VERSION 5.8 ;
BUSBITCHARS "[]" ;
DIVIDERCHAR "/" ;
UNITS
    DATABASE MICRONS 1000 ;
END UNITS

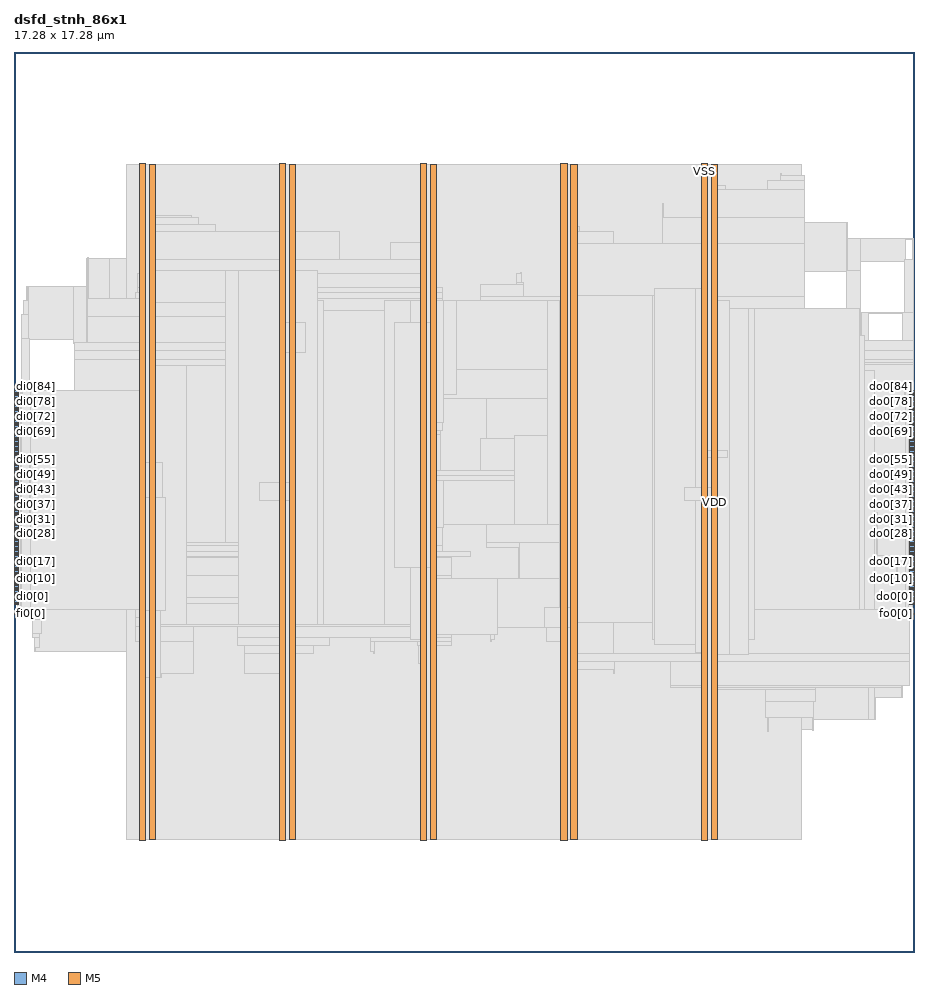
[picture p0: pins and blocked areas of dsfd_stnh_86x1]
MACRO dsfd_stnh_86x1
  FOREIGN dsfd_stnh_86x1 0 0 ;
  CLASS BLOCK ;
  SIZE 17.28 BY 17.28 ;
  PIN di0[0]
    DIRECTION INPUT ;
    USE SIGNAL ;
    PORT
      LAYER M4 ;
        RECT  0 6.672 0.084 6.696 ;
    END
  END di0[0]
  PIN di0[10]
    DIRECTION INPUT ;
    USE SIGNAL ;
    PORT
      LAYER M4 ;
        RECT  0 7.152 0.084 7.176 ;
    END
  END di0[10]
  PIN di0[11]
    DIRECTION INPUT ;
    USE SIGNAL ;
    PORT
      LAYER M4 ;
        RECT  0 7.2 0.084 7.224 ;
    END
  END di0[11]
  PIN di0[12]
    DIRECTION INPUT ;
    USE SIGNAL ;
    PORT
      LAYER M4 ;
        RECT  0 7.248 0.084 7.272 ;
    END
  END di0[12]
  PIN di0[13]
    DIRECTION INPUT ;
    USE SIGNAL ;
    PORT
      LAYER M4 ;
        RECT  0 7.296 0.084 7.32 ;
    END
  END di0[13]
  PIN di0[14]
    DIRECTION INPUT ;
    USE SIGNAL ;
    PORT
      LAYER M4 ;
        RECT  0 7.344 0.084 7.368 ;
    END
  END di0[14]
  PIN di0[15]
    DIRECTION INPUT ;
    USE SIGNAL ;
    PORT
      LAYER M4 ;
        RECT  0 7.392 0.084 7.416 ;
    END
  END di0[15]
  PIN di0[16]
    DIRECTION INPUT ;
    USE SIGNAL ;
    PORT
      LAYER M4 ;
        RECT  0 7.44 0.084 7.464 ;
    END
  END di0[16]
  PIN di0[17]
    DIRECTION INPUT ;
    USE SIGNAL ;
    PORT
      LAYER M4 ;
        RECT  0 7.488 0.084 7.512 ;
    END
  END di0[17]
  PIN di0[18]
    DIRECTION INPUT ;
    USE SIGNAL ;
    PORT
      LAYER M4 ;
        RECT  0 7.536 0.084 7.56 ;
    END
  END di0[18]
  PIN di0[19]
    DIRECTION INPUT ;
    USE SIGNAL ;
    PORT
      LAYER M4 ;
        RECT  0 7.584 0.084 7.608 ;
    END
  END di0[19]
  PIN di0[1]
    DIRECTION INPUT ;
    USE SIGNAL ;
    PORT
      LAYER M4 ;
        RECT  0 6.72 0.084 6.744 ;
    END
  END di0[1]
  PIN di0[20]
    DIRECTION INPUT ;
    USE SIGNAL ;
    PORT
      LAYER M4 ;
        RECT  0 7.632 0.084 7.656 ;
    END
  END di0[20]
  PIN di0[21]
    DIRECTION INPUT ;
    USE SIGNAL ;
    PORT
      LAYER M4 ;
        RECT  0 7.68 0.084 7.704 ;
    END
  END di0[21]
  PIN di0[22]
    DIRECTION INPUT ;
    USE SIGNAL ;
    PORT
      LAYER M4 ;
        RECT  0 7.728 0.084 7.752 ;
    END
  END di0[22]
  PIN di0[23]
    DIRECTION INPUT ;
    USE SIGNAL ;
    PORT
      LAYER M4 ;
        RECT  0 7.776 0.084 7.8 ;
    END
  END di0[23]
  PIN di0[24]
    DIRECTION INPUT ;
    USE SIGNAL ;
    PORT
      LAYER M4 ;
        RECT  0 7.824 0.084 7.848 ;
    END
  END di0[24]
  PIN di0[25]
    DIRECTION INPUT ;
    USE SIGNAL ;
    PORT
      LAYER M4 ;
        RECT  0 7.872 0.084 7.896 ;
    END
  END di0[25]
  PIN di0[26]
    DIRECTION INPUT ;
    USE SIGNAL ;
    PORT
      LAYER M4 ;
        RECT  0 7.92 0.084 7.944 ;
    END
  END di0[26]
  PIN di0[27]
    DIRECTION INPUT ;
    USE SIGNAL ;
    PORT
      LAYER M4 ;
        RECT  0 7.968 0.084 7.992 ;
    END
  END di0[27]
  PIN di0[28]
    DIRECTION INPUT ;
    USE SIGNAL ;
    PORT
      LAYER M4 ;
        RECT  0 8.016 0.084 8.04 ;
    END
  END di0[28]
  PIN di0[29]
    DIRECTION INPUT ;
    USE SIGNAL ;
    PORT
      LAYER M4 ;
        RECT  0 8.064 0.084 8.088 ;
    END
  END di0[29]
  PIN di0[2]
    DIRECTION INPUT ;
    USE SIGNAL ;
    PORT
      LAYER M4 ;
        RECT  0 6.768 0.084 6.792 ;
    END
  END di0[2]
  PIN di0[30]
    DIRECTION INPUT ;
    USE SIGNAL ;
    PORT
      LAYER M4 ;
        RECT  0 8.112 0.084 8.136 ;
    END
  END di0[30]
  PIN di0[31]
    DIRECTION INPUT ;
    USE SIGNAL ;
    PORT
      LAYER M4 ;
        RECT  0 8.16 0.084 8.184 ;
    END
  END di0[31]
  PIN di0[32]
    DIRECTION INPUT ;
    USE SIGNAL ;
    PORT
      LAYER M4 ;
        RECT  0 8.208 0.084 8.232 ;
    END
  END di0[32]
  PIN di0[33]
    DIRECTION INPUT ;
    USE SIGNAL ;
    PORT
      LAYER M4 ;
        RECT  0 8.256 0.084 8.28 ;
    END
  END di0[33]
  PIN di0[34]
    DIRECTION INPUT ;
    USE SIGNAL ;
    PORT
      LAYER M4 ;
        RECT  0 8.304 0.084 8.328 ;
    END
  END di0[34]
  PIN di0[35]
    DIRECTION INPUT ;
    USE SIGNAL ;
    PORT
      LAYER M4 ;
        RECT  0 8.352 0.084 8.376 ;
    END
  END di0[35]
  PIN di0[36]
    DIRECTION INPUT ;
    USE SIGNAL ;
    PORT
      LAYER M4 ;
        RECT  0 8.4 0.084 8.424 ;
    END
  END di0[36]
  PIN di0[37]
    DIRECTION INPUT ;
    USE SIGNAL ;
    PORT
      LAYER M4 ;
        RECT  0 8.448 0.084 8.472 ;
    END
  END di0[37]
  PIN di0[38]
    DIRECTION INPUT ;
    USE SIGNAL ;
    PORT
      LAYER M4 ;
        RECT  0 8.496 0.084 8.52 ;
    END
  END di0[38]
  PIN di0[39]
    DIRECTION INPUT ;
    USE SIGNAL ;
    PORT
      LAYER M4 ;
        RECT  0 8.544 0.084 8.568 ;
    END
  END di0[39]
  PIN di0[3]
    DIRECTION INPUT ;
    USE SIGNAL ;
    PORT
      LAYER M4 ;
        RECT  0 6.816 0.084 6.84 ;
    END
  END di0[3]
  PIN di0[40]
    DIRECTION INPUT ;
    USE SIGNAL ;
    PORT
      LAYER M4 ;
        RECT  0 8.592 0.084 8.616 ;
    END
  END di0[40]
  PIN di0[41]
    DIRECTION INPUT ;
    USE SIGNAL ;
    PORT
      LAYER M4 ;
        RECT  0 8.64 0.084 8.664 ;
    END
  END di0[41]
  PIN di0[42]
    DIRECTION INPUT ;
    USE SIGNAL ;
    PORT
      LAYER M4 ;
        RECT  0 8.688 0.084 8.712 ;
    END
  END di0[42]
  PIN di0[43]
    DIRECTION INPUT ;
    USE SIGNAL ;
    PORT
      LAYER M4 ;
        RECT  0 8.736 0.084 8.76 ;
    END
  END di0[43]
  PIN di0[44]
    DIRECTION INPUT ;
    USE SIGNAL ;
    PORT
      LAYER M4 ;
        RECT  0 8.784 0.084 8.808 ;
    END
  END di0[44]
  PIN di0[45]
    DIRECTION INPUT ;
    USE SIGNAL ;
    PORT
      LAYER M4 ;
        RECT  0 8.832 0.084 8.856 ;
    END
  END di0[45]
  PIN di0[46]
    DIRECTION INPUT ;
    USE SIGNAL ;
    PORT
      LAYER M4 ;
        RECT  0 8.88 0.084 8.904 ;
    END
  END di0[46]
  PIN di0[47]
    DIRECTION INPUT ;
    USE SIGNAL ;
    PORT
      LAYER M4 ;
        RECT  0 8.928 0.084 8.952 ;
    END
  END di0[47]
  PIN di0[48]
    DIRECTION INPUT ;
    USE SIGNAL ;
    PORT
      LAYER M4 ;
        RECT  0 8.976 0.084 9 ;
    END
  END di0[48]
  PIN di0[49]
    DIRECTION INPUT ;
    USE SIGNAL ;
    PORT
      LAYER M4 ;
        RECT  0 9.024 0.084 9.048 ;
    END
  END di0[49]
  PIN di0[4]
    DIRECTION INPUT ;
    USE SIGNAL ;
    PORT
      LAYER M4 ;
        RECT  0 6.864 0.084 6.888 ;
    END
  END di0[4]
  PIN di0[50]
    DIRECTION INPUT ;
    USE SIGNAL ;
    PORT
      LAYER M4 ;
        RECT  0 9.072 0.084 9.096 ;
    END
  END di0[50]
  PIN di0[51]
    DIRECTION INPUT ;
    USE SIGNAL ;
    PORT
      LAYER M4 ;
        RECT  0 9.12 0.084 9.144 ;
    END
  END di0[51]
  PIN di0[52]
    DIRECTION INPUT ;
    USE SIGNAL ;
    PORT
      LAYER M4 ;
        RECT  0 9.168 0.084 9.192 ;
    END
  END di0[52]
  PIN di0[53]
    DIRECTION INPUT ;
    USE SIGNAL ;
    PORT
      LAYER M4 ;
        RECT  0 9.216 0.084 9.24 ;
    END
  END di0[53]
  PIN di0[54]
    DIRECTION INPUT ;
    USE SIGNAL ;
    PORT
      LAYER M4 ;
        RECT  0 9.264 0.084 9.288 ;
    END
  END di0[54]
  PIN di0[55]
    DIRECTION INPUT ;
    USE SIGNAL ;
    PORT
      LAYER M4 ;
        RECT  0 9.312 0.084 9.336 ;
    END
  END di0[55]
  PIN di0[56]
    DIRECTION INPUT ;
    USE SIGNAL ;
    PORT
      LAYER M4 ;
        RECT  0 9.36 0.084 9.384 ;
    END
  END di0[56]
  PIN di0[57]
    DIRECTION INPUT ;
    USE SIGNAL ;
    PORT
      LAYER M4 ;
        RECT  0 9.408 0.084 9.432 ;
    END
  END di0[57]
  PIN di0[58]
    DIRECTION INPUT ;
    USE SIGNAL ;
    PORT
      LAYER M4 ;
        RECT  0 9.456 0.084 9.48 ;
    END
  END di0[58]
  PIN di0[59]
    DIRECTION INPUT ;
    USE SIGNAL ;
    PORT
      LAYER M4 ;
        RECT  0 9.504 0.084 9.528 ;
    END
  END di0[59]
  PIN di0[5]
    DIRECTION INPUT ;
    USE SIGNAL ;
    PORT
      LAYER M4 ;
        RECT  0 6.912 0.084 6.936 ;
    END
  END di0[5]
  PIN di0[60]
    DIRECTION INPUT ;
    USE SIGNAL ;
    PORT
      LAYER M4 ;
        RECT  0 9.552 0.084 9.576 ;
    END
  END di0[60]
  PIN di0[61]
    DIRECTION INPUT ;
    USE SIGNAL ;
    PORT
      LAYER M4 ;
        RECT  0 9.6 0.084 9.624 ;
    END
  END di0[61]
  PIN di0[62]
    DIRECTION INPUT ;
    USE SIGNAL ;
    PORT
      LAYER M4 ;
        RECT  0 9.648 0.084 9.672 ;
    END
  END di0[62]
  PIN di0[63]
    DIRECTION INPUT ;
    USE SIGNAL ;
    PORT
      LAYER M4 ;
        RECT  0 9.696 0.084 9.72 ;
    END
  END di0[63]
  PIN di0[64]
    DIRECTION INPUT ;
    USE SIGNAL ;
    PORT
      LAYER M4 ;
        RECT  0 9.744 0.084 9.768 ;
    END
  END di0[64]
  PIN di0[65]
    DIRECTION INPUT ;
    USE SIGNAL ;
    PORT
      LAYER M4 ;
        RECT  0 9.792 0.084 9.816 ;
    END
  END di0[65]
  PIN di0[66]
    DIRECTION INPUT ;
    USE SIGNAL ;
    PORT
      LAYER M4 ;
        RECT  0 9.84 0.084 9.864 ;
    END
  END di0[66]
  PIN di0[67]
    DIRECTION INPUT ;
    USE SIGNAL ;
    PORT
      LAYER M4 ;
        RECT  0 9.888 0.084 9.912 ;
    END
  END di0[67]
  PIN di0[68]
    DIRECTION INPUT ;
    USE SIGNAL ;
    PORT
      LAYER M4 ;
        RECT  0 9.936 0.084 9.96 ;
    END
  END di0[68]
  PIN di0[69]
    DIRECTION INPUT ;
    USE SIGNAL ;
    PORT
      LAYER M4 ;
        RECT  0 9.984 0.084 10.008 ;
    END
  END di0[69]
  PIN di0[6]
    DIRECTION INPUT ;
    USE SIGNAL ;
    PORT
      LAYER M4 ;
        RECT  0 6.96 0.084 6.984 ;
    END
  END di0[6]
  PIN di0[70]
    DIRECTION INPUT ;
    USE SIGNAL ;
    PORT
      LAYER M4 ;
        RECT  0 10.032 0.084 10.056 ;
    END
  END di0[70]
  PIN di0[71]
    DIRECTION INPUT ;
    USE SIGNAL ;
    PORT
      LAYER M4 ;
        RECT  0 10.08 0.084 10.104 ;
    END
  END di0[71]
  PIN di0[72]
    DIRECTION INPUT ;
    USE SIGNAL ;
    PORT
      LAYER M4 ;
        RECT  0 10.128 0.084 10.152 ;
    END
  END di0[72]
  PIN di0[73]
    DIRECTION INPUT ;
    USE SIGNAL ;
    PORT
      LAYER M4 ;
        RECT  0 10.176 0.084 10.2 ;
    END
  END di0[73]
  PIN di0[74]
    DIRECTION INPUT ;
    USE SIGNAL ;
    PORT
      LAYER M4 ;
        RECT  0 10.224 0.084 10.248 ;
    END
  END di0[74]
  PIN di0[75]
    DIRECTION INPUT ;
    USE SIGNAL ;
    PORT
      LAYER M4 ;
        RECT  0 10.272 0.084 10.296 ;
    END
  END di0[75]
  PIN di0[76]
    DIRECTION INPUT ;
    USE SIGNAL ;
    PORT
      LAYER M4 ;
        RECT  0 10.32 0.084 10.344 ;
    END
  END di0[76]
  PIN di0[77]
    DIRECTION INPUT ;
    USE SIGNAL ;
    PORT
      LAYER M4 ;
        RECT  0 10.368 0.084 10.392 ;
    END
  END di0[77]
  PIN di0[78]
    DIRECTION INPUT ;
    USE SIGNAL ;
    PORT
      LAYER M4 ;
        RECT  0 10.416 0.084 10.44 ;
    END
  END di0[78]
  PIN di0[79]
    DIRECTION INPUT ;
    USE SIGNAL ;
    PORT
      LAYER M4 ;
        RECT  0 10.464 0.084 10.488 ;
    END
  END di0[79]
  PIN di0[7]
    DIRECTION INPUT ;
    USE SIGNAL ;
    PORT
      LAYER M4 ;
        RECT  0 7.008 0.084 7.032 ;
    END
  END di0[7]
  PIN di0[80]
    DIRECTION INPUT ;
    USE SIGNAL ;
    PORT
      LAYER M4 ;
        RECT  0 10.512 0.084 10.536 ;
    END
  END di0[80]
  PIN di0[81]
    DIRECTION INPUT ;
    USE SIGNAL ;
    PORT
      LAYER M4 ;
        RECT  0 10.56 0.084 10.584 ;
    END
  END di0[81]
  PIN di0[82]
    DIRECTION INPUT ;
    USE SIGNAL ;
    PORT
      LAYER M4 ;
        RECT  0 10.608 0.084 10.632 ;
    END
  END di0[82]
  PIN di0[83]
    DIRECTION INPUT ;
    USE SIGNAL ;
    PORT
      LAYER M4 ;
        RECT  0 10.656 0.084 10.68 ;
    END
  END di0[83]
  PIN di0[84]
    DIRECTION INPUT ;
    USE SIGNAL ;
    PORT
      LAYER M4 ;
        RECT  0 10.704 0.084 10.728 ;
    END
  END di0[84]
  PIN di0[85]
    DIRECTION INPUT ;
    USE SIGNAL ;
    PORT
      LAYER M4 ;
        RECT  0 10.752 0.084 10.776 ;
    END
  END di0[85]
  PIN di0[8]
    DIRECTION INPUT ;
    USE SIGNAL ;
    PORT
      LAYER M4 ;
        RECT  0 7.056 0.084 7.08 ;
    END
  END di0[8]
  PIN di0[9]
    DIRECTION INPUT ;
    USE SIGNAL ;
    PORT
      LAYER M4 ;
        RECT  0 7.104 0.084 7.128 ;
    END
  END di0[9]
  PIN do0[0]
    DIRECTION OUTPUT ;
    USE SIGNAL ;
    PORT
      LAYER M4 ;
        RECT  17.196 6.672 17.28 6.696 ;
    END
  END do0[0]
  PIN do0[10]
    DIRECTION OUTPUT ;
    USE SIGNAL ;
    PORT
      LAYER M4 ;
        RECT  17.196 7.152 17.28 7.176 ;
    END
  END do0[10]
  PIN do0[11]
    DIRECTION OUTPUT ;
    USE SIGNAL ;
    PORT
      LAYER M4 ;
        RECT  17.196 7.2 17.28 7.224 ;
    END
  END do0[11]
  PIN do0[12]
    DIRECTION OUTPUT ;
    USE SIGNAL ;
    PORT
      LAYER M4 ;
        RECT  17.196 7.248 17.28 7.272 ;
    END
  END do0[12]
  PIN do0[13]
    DIRECTION OUTPUT ;
    USE SIGNAL ;
    PORT
      LAYER M4 ;
        RECT  17.196 7.296 17.28 7.32 ;
    END
  END do0[13]
  PIN do0[14]
    DIRECTION OUTPUT ;
    USE SIGNAL ;
    PORT
      LAYER M4 ;
        RECT  17.196 7.344 17.28 7.368 ;
    END
  END do0[14]
  PIN do0[15]
    DIRECTION OUTPUT ;
    USE SIGNAL ;
    PORT
      LAYER M4 ;
        RECT  17.196 7.392 17.28 7.416 ;
    END
  END do0[15]
  PIN do0[16]
    DIRECTION OUTPUT ;
    USE SIGNAL ;
    PORT
      LAYER M4 ;
        RECT  17.196 7.44 17.28 7.464 ;
    END
  END do0[16]
  PIN do0[17]
    DIRECTION OUTPUT ;
    USE SIGNAL ;
    PORT
      LAYER M4 ;
        RECT  17.196 7.488 17.28 7.512 ;
    END
  END do0[17]
  PIN do0[18]
    DIRECTION OUTPUT ;
    USE SIGNAL ;
    PORT
      LAYER M4 ;
        RECT  17.196 7.536 17.28 7.56 ;
    END
  END do0[18]
  PIN do0[19]
    DIRECTION OUTPUT ;
    USE SIGNAL ;
    PORT
      LAYER M4 ;
        RECT  17.196 7.584 17.28 7.608 ;
    END
  END do0[19]
  PIN do0[1]
    DIRECTION OUTPUT ;
    USE SIGNAL ;
    PORT
      LAYER M4 ;
        RECT  17.196 6.72 17.28 6.744 ;
    END
  END do0[1]
  PIN do0[20]
    DIRECTION OUTPUT ;
    USE SIGNAL ;
    PORT
      LAYER M4 ;
        RECT  17.196 7.632 17.28 7.656 ;
    END
  END do0[20]
  PIN do0[21]
    DIRECTION OUTPUT ;
    USE SIGNAL ;
    PORT
      LAYER M4 ;
        RECT  17.196 7.68 17.28 7.704 ;
    END
  END do0[21]
  PIN do0[22]
    DIRECTION OUTPUT ;
    USE SIGNAL ;
    PORT
      LAYER M4 ;
        RECT  17.196 7.728 17.28 7.752 ;
    END
  END do0[22]
  PIN do0[23]
    DIRECTION OUTPUT ;
    USE SIGNAL ;
    PORT
      LAYER M4 ;
        RECT  17.196 7.776 17.28 7.8 ;
    END
  END do0[23]
  PIN do0[24]
    DIRECTION OUTPUT ;
    USE SIGNAL ;
    PORT
      LAYER M4 ;
        RECT  17.196 7.824 17.28 7.848 ;
    END
  END do0[24]
  PIN do0[25]
    DIRECTION OUTPUT ;
    USE SIGNAL ;
    PORT
      LAYER M4 ;
        RECT  17.196 7.872 17.28 7.896 ;
    END
  END do0[25]
  PIN do0[26]
    DIRECTION OUTPUT ;
    USE SIGNAL ;
    PORT
      LAYER M4 ;
        RECT  17.196 7.92 17.28 7.944 ;
    END
  END do0[26]
  PIN do0[27]
    DIRECTION OUTPUT ;
    USE SIGNAL ;
    PORT
      LAYER M4 ;
        RECT  17.196 7.968 17.28 7.992 ;
    END
  END do0[27]
  PIN do0[28]
    DIRECTION OUTPUT ;
    USE SIGNAL ;
    PORT
      LAYER M4 ;
        RECT  17.196 8.016 17.28 8.04 ;
    END
  END do0[28]
  PIN do0[29]
    DIRECTION OUTPUT ;
    USE SIGNAL ;
    PORT
      LAYER M4 ;
        RECT  17.196 8.064 17.28 8.088 ;
    END
  END do0[29]
  PIN do0[2]
    DIRECTION OUTPUT ;
    USE SIGNAL ;
    PORT
      LAYER M4 ;
        RECT  17.196 6.768 17.28 6.792 ;
    END
  END do0[2]
  PIN do0[30]
    DIRECTION OUTPUT ;
    USE SIGNAL ;
    PORT
      LAYER M4 ;
        RECT  17.196 8.112 17.28 8.136 ;
    END
  END do0[30]
  PIN do0[31]
    DIRECTION OUTPUT ;
    USE SIGNAL ;
    PORT
      LAYER M4 ;
        RECT  17.196 8.16 17.28 8.184 ;
    END
  END do0[31]
  PIN do0[32]
    DIRECTION OUTPUT ;
    USE SIGNAL ;
    PORT
      LAYER M4 ;
        RECT  17.196 8.208 17.28 8.232 ;
    END
  END do0[32]
  PIN do0[33]
    DIRECTION OUTPUT ;
    USE SIGNAL ;
    PORT
      LAYER M4 ;
        RECT  17.196 8.256 17.28 8.28 ;
    END
  END do0[33]
  PIN do0[34]
    DIRECTION OUTPUT ;
    USE SIGNAL ;
    PORT
      LAYER M4 ;
        RECT  17.196 8.304 17.28 8.328 ;
    END
  END do0[34]
  PIN do0[35]
    DIRECTION OUTPUT ;
    USE SIGNAL ;
    PORT
      LAYER M4 ;
        RECT  17.196 8.352 17.28 8.376 ;
    END
  END do0[35]
  PIN do0[36]
    DIRECTION OUTPUT ;
    USE SIGNAL ;
    PORT
      LAYER M4 ;
        RECT  17.196 8.4 17.28 8.424 ;
    END
  END do0[36]
  PIN do0[37]
    DIRECTION OUTPUT ;
    USE SIGNAL ;
    PORT
      LAYER M4 ;
        RECT  17.196 8.448 17.28 8.472 ;
    END
  END do0[37]
  PIN do0[38]
    DIRECTION OUTPUT ;
    USE SIGNAL ;
    PORT
      LAYER M4 ;
        RECT  17.196 8.496 17.28 8.52 ;
    END
  END do0[38]
  PIN do0[39]
    DIRECTION OUTPUT ;
    USE SIGNAL ;
    PORT
      LAYER M4 ;
        RECT  17.196 8.544 17.28 8.568 ;
    END
  END do0[39]
  PIN do0[3]
    DIRECTION OUTPUT ;
    USE SIGNAL ;
    PORT
      LAYER M4 ;
        RECT  17.196 6.816 17.28 6.84 ;
    END
  END do0[3]
  PIN do0[40]
    DIRECTION OUTPUT ;
    USE SIGNAL ;
    PORT
      LAYER M4 ;
        RECT  17.196 8.592 17.28 8.616 ;
    END
  END do0[40]
  PIN do0[41]
    DIRECTION OUTPUT ;
    USE SIGNAL ;
    PORT
      LAYER M4 ;
        RECT  17.196 8.64 17.28 8.664 ;
    END
  END do0[41]
  PIN do0[42]
    DIRECTION OUTPUT ;
    USE SIGNAL ;
    PORT
      LAYER M4 ;
        RECT  17.196 8.688 17.28 8.712 ;
    END
  END do0[42]
  PIN do0[43]
    DIRECTION OUTPUT ;
    USE SIGNAL ;
    PORT
      LAYER M4 ;
        RECT  17.196 8.736 17.28 8.76 ;
    END
  END do0[43]
  PIN do0[44]
    DIRECTION OUTPUT ;
    USE SIGNAL ;
    PORT
      LAYER M4 ;
        RECT  17.196 8.784 17.28 8.808 ;
    END
  END do0[44]
  PIN do0[45]
    DIRECTION OUTPUT ;
    USE SIGNAL ;
    PORT
      LAYER M4 ;
        RECT  17.196 8.832 17.28 8.856 ;
    END
  END do0[45]
  PIN do0[46]
    DIRECTION OUTPUT ;
    USE SIGNAL ;
    PORT
      LAYER M4 ;
        RECT  17.196 8.88 17.28 8.904 ;
    END
  END do0[46]
  PIN do0[47]
    DIRECTION OUTPUT ;
    USE SIGNAL ;
    PORT
      LAYER M4 ;
        RECT  17.196 8.928 17.28 8.952 ;
    END
  END do0[47]
  PIN do0[48]
    DIRECTION OUTPUT ;
    USE SIGNAL ;
    PORT
      LAYER M4 ;
        RECT  17.196 8.976 17.28 9 ;
    END
  END do0[48]
  PIN do0[49]
    DIRECTION OUTPUT ;
    USE SIGNAL ;
    PORT
      LAYER M4 ;
        RECT  17.196 9.024 17.28 9.048 ;
    END
  END do0[49]
  PIN do0[4]
    DIRECTION OUTPUT ;
    USE SIGNAL ;
    PORT
      LAYER M4 ;
        RECT  17.196 6.864 17.28 6.888 ;
    END
  END do0[4]
  PIN do0[50]
    DIRECTION OUTPUT ;
    USE SIGNAL ;
    PORT
      LAYER M4 ;
        RECT  17.196 9.072 17.28 9.096 ;
    END
  END do0[50]
  PIN do0[51]
    DIRECTION OUTPUT ;
    USE SIGNAL ;
    PORT
      LAYER M4 ;
        RECT  17.196 9.12 17.28 9.144 ;
    END
  END do0[51]
  PIN do0[52]
    DIRECTION OUTPUT ;
    USE SIGNAL ;
    PORT
      LAYER M4 ;
        RECT  17.196 9.168 17.28 9.192 ;
    END
  END do0[52]
  PIN do0[53]
    DIRECTION OUTPUT ;
    USE SIGNAL ;
    PORT
      LAYER M4 ;
        RECT  17.196 9.216 17.28 9.24 ;
    END
  END do0[53]
  PIN do0[54]
    DIRECTION OUTPUT ;
    USE SIGNAL ;
    PORT
      LAYER M4 ;
        RECT  17.196 9.264 17.28 9.288 ;
    END
  END do0[54]
  PIN do0[55]
    DIRECTION OUTPUT ;
    USE SIGNAL ;
    PORT
      LAYER M4 ;
        RECT  17.196 9.312 17.28 9.336 ;
    END
  END do0[55]
  PIN do0[56]
    DIRECTION OUTPUT ;
    USE SIGNAL ;
    PORT
      LAYER M4 ;
        RECT  17.196 9.36 17.28 9.384 ;
    END
  END do0[56]
  PIN do0[57]
    DIRECTION OUTPUT ;
    USE SIGNAL ;
    PORT
      LAYER M4 ;
        RECT  17.196 9.408 17.28 9.432 ;
    END
  END do0[57]
  PIN do0[58]
    DIRECTION OUTPUT ;
    USE SIGNAL ;
    PORT
      LAYER M4 ;
        RECT  17.196 9.456 17.28 9.48 ;
    END
  END do0[58]
  PIN do0[59]
    DIRECTION OUTPUT ;
    USE SIGNAL ;
    PORT
      LAYER M4 ;
        RECT  17.196 9.504 17.28 9.528 ;
    END
  END do0[59]
  PIN do0[5]
    DIRECTION OUTPUT ;
    USE SIGNAL ;
    PORT
      LAYER M4 ;
        RECT  17.196 6.912 17.28 6.936 ;
    END
  END do0[5]
  PIN do0[60]
    DIRECTION OUTPUT ;
    USE SIGNAL ;
    PORT
      LAYER M4 ;
        RECT  17.196 9.552 17.28 9.576 ;
    END
  END do0[60]
  PIN do0[61]
    DIRECTION OUTPUT ;
    USE SIGNAL ;
    PORT
      LAYER M4 ;
        RECT  17.196 9.6 17.28 9.624 ;
    END
  END do0[61]
  PIN do0[62]
    DIRECTION OUTPUT ;
    USE SIGNAL ;
    PORT
      LAYER M4 ;
        RECT  17.196 9.648 17.28 9.672 ;
    END
  END do0[62]
  PIN do0[63]
    DIRECTION OUTPUT ;
    USE SIGNAL ;
    PORT
      LAYER M4 ;
        RECT  17.196 9.696 17.28 9.72 ;
    END
  END do0[63]
  PIN do0[64]
    DIRECTION OUTPUT ;
    USE SIGNAL ;
    PORT
      LAYER M4 ;
        RECT  17.196 9.744 17.28 9.768 ;
    END
  END do0[64]
  PIN do0[65]
    DIRECTION OUTPUT ;
    USE SIGNAL ;
    PORT
      LAYER M4 ;
        RECT  17.196 9.792 17.28 9.816 ;
    END
  END do0[65]
  PIN do0[66]
    DIRECTION OUTPUT ;
    USE SIGNAL ;
    PORT
      LAYER M4 ;
        RECT  17.196 9.84 17.28 9.864 ;
    END
  END do0[66]
  PIN do0[67]
    DIRECTION OUTPUT ;
    USE SIGNAL ;
    PORT
      LAYER M4 ;
        RECT  17.196 9.888 17.28 9.912 ;
    END
  END do0[67]
  PIN do0[68]
    DIRECTION OUTPUT ;
    USE SIGNAL ;
    PORT
      LAYER M4 ;
        RECT  17.196 9.936 17.28 9.96 ;
    END
  END do0[68]
  PIN do0[69]
    DIRECTION OUTPUT ;
    USE SIGNAL ;
    PORT
      LAYER M4 ;
        RECT  17.196 9.984 17.28 10.008 ;
    END
  END do0[69]
  PIN do0[6]
    DIRECTION OUTPUT ;
    USE SIGNAL ;
    PORT
      LAYER M4 ;
        RECT  17.196 6.96 17.28 6.984 ;
    END
  END do0[6]
  PIN do0[70]
    DIRECTION OUTPUT ;
    USE SIGNAL ;
    PORT
      LAYER M4 ;
        RECT  17.196 10.032 17.28 10.056 ;
    END
  END do0[70]
  PIN do0[71]
    DIRECTION OUTPUT ;
    USE SIGNAL ;
    PORT
      LAYER M4 ;
        RECT  17.196 10.08 17.28 10.104 ;
    END
  END do0[71]
  PIN do0[72]
    DIRECTION OUTPUT ;
    USE SIGNAL ;
    PORT
      LAYER M4 ;
        RECT  17.196 10.128 17.28 10.152 ;
    END
  END do0[72]
  PIN do0[73]
    DIRECTION OUTPUT ;
    USE SIGNAL ;
    PORT
      LAYER M4 ;
        RECT  17.196 10.176 17.28 10.2 ;
    END
  END do0[73]
  PIN do0[74]
    DIRECTION OUTPUT ;
    USE SIGNAL ;
    PORT
      LAYER M4 ;
        RECT  17.196 10.224 17.28 10.248 ;
    END
  END do0[74]
  PIN do0[75]
    DIRECTION OUTPUT ;
    USE SIGNAL ;
    PORT
      LAYER M4 ;
        RECT  17.196 10.272 17.28 10.296 ;
    END
  END do0[75]
  PIN do0[76]
    DIRECTION OUTPUT ;
    USE SIGNAL ;
    PORT
      LAYER M4 ;
        RECT  17.196 10.32 17.28 10.344 ;
    END
  END do0[76]
  PIN do0[77]
    DIRECTION OUTPUT ;
    USE SIGNAL ;
    PORT
      LAYER M4 ;
        RECT  17.196 10.368 17.28 10.392 ;
    END
  END do0[77]
  PIN do0[78]
    DIRECTION OUTPUT ;
    USE SIGNAL ;
    PORT
      LAYER M4 ;
        RECT  17.196 10.416 17.28 10.44 ;
    END
  END do0[78]
  PIN do0[79]
    DIRECTION OUTPUT ;
    USE SIGNAL ;
    PORT
      LAYER M4 ;
        RECT  17.196 10.464 17.28 10.488 ;
    END
  END do0[79]
  PIN do0[7]
    DIRECTION OUTPUT ;
    USE SIGNAL ;
    PORT
      LAYER M4 ;
        RECT  17.196 7.008 17.28 7.032 ;
    END
  END do0[7]
  PIN do0[80]
    DIRECTION OUTPUT ;
    USE SIGNAL ;
    PORT
      LAYER M4 ;
        RECT  17.196 10.512 17.28 10.536 ;
    END
  END do0[80]
  PIN do0[81]
    DIRECTION OUTPUT ;
    USE SIGNAL ;
    PORT
      LAYER M4 ;
        RECT  17.196 10.56 17.28 10.584 ;
    END
  END do0[81]
  PIN do0[82]
    DIRECTION OUTPUT ;
    USE SIGNAL ;
    PORT
      LAYER M4 ;
        RECT  17.196 10.608 17.28 10.632 ;
    END
  END do0[82]
  PIN do0[83]
    DIRECTION OUTPUT ;
    USE SIGNAL ;
    PORT
      LAYER M4 ;
        RECT  17.196 10.656 17.28 10.68 ;
    END
  END do0[83]
  PIN do0[84]
    DIRECTION OUTPUT ;
    USE SIGNAL ;
    PORT
      LAYER M4 ;
        RECT  17.196 10.704 17.28 10.728 ;
    END
  END do0[84]
  PIN do0[85]
    DIRECTION OUTPUT ;
    USE SIGNAL ;
    PORT
      LAYER M4 ;
        RECT  17.196 10.752 17.28 10.776 ;
    END
  END do0[85]
  PIN do0[8]
    DIRECTION OUTPUT ;
    USE SIGNAL ;
    PORT
      LAYER M4 ;
        RECT  17.196 7.056 17.28 7.08 ;
    END
  END do0[8]
  PIN do0[9]
    DIRECTION OUTPUT ;
    USE SIGNAL ;
    PORT
      LAYER M4 ;
        RECT  17.196 7.104 17.28 7.128 ;
    END
  END do0[9]
  PIN fi0[0]
    DIRECTION INPUT ;
    USE SIGNAL ;
    PORT
      LAYER M4 ;
        RECT  0 6.48 0.084 6.504 ;
    END
  END fi0[0]
  PIN fo0[0]
    DIRECTION OUTPUT ;
    USE SIGNAL ;
    PORT
      LAYER M4 ;
        RECT  17.196 6.48 17.28 6.504 ;
    END
  END fo0[0]
  PIN VDD
    DIRECTION INOUT ;
    USE POWER ;
    PORT
      LAYER M5 ;
        RECT  13.392 2.151 13.512 15.129 ;
        RECT  10.692 2.151 10.812 15.129 ;
        RECT  7.992 2.151 8.112 15.129 ;
        RECT  5.292 2.151 5.412 15.129 ;
        RECT  2.592 2.151 2.712 15.129 ;
    END
  END VDD
  PIN VSS
    DIRECTION INOUT ;
    USE GROUND ;
    PORT
      LAYER M5 ;
        RECT  13.2 2.137 13.32 15.143 ;
        RECT  10.5 2.137 10.62 15.143 ;
        RECT  7.8 2.137 7.92 15.143 ;
        RECT  5.1 2.137 5.22 15.143 ;
        RECT  2.4 2.137 2.52 15.143 ;
    END
  END VSS
  OBS
    LAYER RVTN ;
     RECT  2.16 2.16 15.12 2.295 ;
     RECT  2.16 2.565 15.12 2.835 ;
     RECT  2.16 3.105 15.12 3.375 ;
     RECT  2.16 3.645 15.12 3.915 ;
     RECT  2.16 4.185 15.12 4.455 ;
     RECT  2.16 4.725 15.12 4.995 ;
     RECT  2.16 5.265 15.12 5.535 ;
     RECT  2.16 5.805 15.12 6.075 ;
     RECT  2.16 6.345 15.12 6.615 ;
     RECT  2.16 6.885 15.12 7.155 ;
     RECT  2.16 7.425 15.12 7.695 ;
     RECT  2.16 7.965 15.12 8.235 ;
     RECT  2.16 8.505 15.12 8.775 ;
     RECT  2.16 9.045 15.12 9.315 ;
     RECT  2.16 9.585 15.12 9.855 ;
     RECT  2.16 10.125 15.12 10.395 ;
     RECT  2.16 10.665 15.12 10.935 ;
     RECT  2.16 11.205 15.12 11.475 ;
     RECT  2.16 11.745 15.12 12.015 ;
     RECT  2.16 12.285 15.12 12.555 ;
     RECT  2.16 12.825 15.12 13.095 ;
     RECT  2.16 13.365 15.12 13.635 ;
     RECT  2.16 13.905 15.12 14.175 ;
     RECT  2.16 14.445 15.12 14.715 ;
     RECT  2.16 14.985 15.12 15.12 ;
    LAYER RVTP ;
     RECT  2.16 2.295 15.12 2.565 ;
     RECT  2.16 2.835 15.12 3.105 ;
     RECT  2.16 3.375 15.12 3.645 ;
     RECT  2.16 3.915 15.12 4.185 ;
     RECT  2.16 4.455 15.12 4.725 ;
     RECT  2.16 4.995 15.12 5.265 ;
     RECT  2.16 5.535 15.12 5.805 ;
     RECT  2.16 6.075 15.12 6.345 ;
     RECT  2.16 6.615 15.12 6.885 ;
     RECT  2.16 7.155 15.12 7.425 ;
     RECT  2.16 7.695 15.12 7.965 ;
     RECT  2.16 8.235 15.12 8.505 ;
     RECT  2.16 8.775 15.12 9.045 ;
     RECT  2.16 9.315 15.12 9.585 ;
     RECT  2.16 9.855 15.12 10.125 ;
     RECT  2.16 10.395 15.12 10.665 ;
     RECT  2.16 10.935 15.12 11.205 ;
     RECT  2.16 11.475 15.12 11.745 ;
     RECT  2.16 12.015 15.12 12.285 ;
     RECT  2.16 12.555 15.12 12.825 ;
     RECT  2.16 13.095 15.12 13.365 ;
     RECT  2.16 13.635 15.12 13.905 ;
     RECT  2.16 14.175 15.12 14.445 ;
     RECT  2.16 14.715 15.12 14.985 ;
    LAYER M1 ;
     RECT  2.16 2.151 15.12 15.129 ;
    LAYER M2 ;
     RECT  0.103 8.361 0.139 8.919 ;
     RECT  0.139 8.172 0.175 8.964 ;
     RECT  0.139 12.222 0.175 12.24 ;
     RECT  0.175 8.172 0.211 9.54 ;
     RECT  0.211 8.172 0.247 9.882 ;
     RECT  0.175 12.222 0.247 12.51 ;
     RECT  0.247 12.222 0.283 12.78 ;
     RECT  0.175 6.696 0.319 6.714 ;
     RECT  0.247 8.172 0.319 9.918 ;
     RECT  0.319 6.696 0.355 6.84 ;
     RECT  0.355 6.048 0.391 6.84 ;
     RECT  0.319 8.172 0.419 10.116 ;
     RECT  0.419 8.244 1.147 10.116 ;
     RECT  0.283 11.754 1.147 12.78 ;
     RECT  1.147 11.682 1.399 12.78 ;
     RECT  1.795 10.908 1.831 10.926 ;
     RECT  1.399 11.682 1.831 13.32 ;
     RECT  0.391 5.778 2.16 6.84 ;
     RECT  1.147 8.208 2.16 10.116 ;
     RECT  1.831 10.908 2.16 13.32 ;
     RECT  2.16 2.151 15.12 15.129 ;
     RECT  15.12 8.316 15.179 9.108 ;
     RECT  15.12 14.886 15.179 14.904 ;
     RECT  15.12 4.266 15.359 6.714 ;
     RECT  15.179 8.316 16.007 8.334 ;
     RECT  15.12 13.068 16.007 14.004 ;
     RECT  15.12 10.836 16.043 12.312 ;
     RECT  15.12 10.026 16.051 10.044 ;
     RECT  16.043 10.836 16.051 12.276 ;
     RECT  16.007 13.068 16.259 13.698 ;
     RECT  16.051 10.026 16.267 12.276 ;
     RECT  15.12 7.47 16.375 7.524 ;
     RECT  16.267 9.981 16.403 12.276 ;
     RECT  15.359 4.464 16.411 6.714 ;
     RECT  16.375 7.47 16.411 7.956 ;
     RECT  15.179 9.09 16.483 9.108 ;
     RECT  16.411 4.464 16.547 7.956 ;
     RECT  16.547 4.896 16.619 7.956 ;
     RECT  16.619 4.896 16.655 6.444 ;
     RECT  16.483 8.784 16.691 9.108 ;
     RECT  16.619 7.2 16.943 7.956 ;
     RECT  16.691 8.856 17.015 9.108 ;
     RECT  16.655 4.896 17.051 6.174 ;
     RECT  17.015 8.856 17.051 9.036 ;
     RECT  16.403 9.981 17.051 11.394 ;
     RECT  17.051 5.121 17.087 5.364 ;
     RECT  16.403 12.258 17.087 12.276 ;
     RECT  17.051 6.156 17.123 6.174 ;
     RECT  16.259 13.266 17.123 13.698 ;
     RECT  17.051 9.981 17.159 11.034 ;
     RECT  17.087 5.121 17.195 5.139 ;
     RECT  16.943 7.2 17.195 7.218 ;
     RECT  17.051 9.018 17.195 9.036 ;
     RECT  17.159 10.521 17.195 10.764 ;
     RECT  17.195 10.521 17.267 10.539 ;
     RECT  17.123 13.68 17.267 13.698 ;
    LAYER M3 ;
     RECT  2.415 2.143 2.505 2.413 ;
     RECT  5.115 2.143 5.205 2.413 ;
     RECT  7.815 2.143 7.905 2.413 ;
     RECT  10.515 2.143 10.605 2.413 ;
     RECT  13.215 2.143 13.305 2.413 ;
     RECT  14.472 4.225 14.49 4.495 ;
     RECT  15.336 4.261 15.354 4.495 ;
     RECT  14.436 4.495 15.354 4.801 ;
     RECT  16.524 4.459 16.542 4.891 ;
     RECT  13.215 2.413 13.497 5.035 ;
     RECT  14.436 4.801 15.39 5.035 ;
     RECT  13.215 5.035 15.39 5.071 ;
     RECT  16.524 4.891 17.046 5.071 ;
     RECT  12.6 5.071 17.046 5.116 ;
     RECT  2.415 2.413 2.697 5.269 ;
     RECT  2.415 5.269 2.826 5.341 ;
     RECT  5.115 2.413 5.397 5.341 ;
     RECT  10.515 2.413 10.797 5.431 ;
     RECT  11.52 5.341 11.538 5.431 ;
     RECT  7.815 2.413 8.097 5.539 ;
     RECT  10.515 5.431 11.538 5.575 ;
     RECT  12.6 5.116 17.19 5.575 ;
     RECT  10.515 5.575 17.19 5.729 ;
     RECT  4.428 5.341 5.397 5.737 ;
     RECT  6.912 5.737 6.93 5.773 ;
     RECT  0.396 5.773 0.414 5.845 ;
     RECT  4.428 5.737 5.742 5.881 ;
     RECT  7.776 5.539 8.097 5.881 ;
     RECT  2.415 5.341 3.438 5.971 ;
     RECT  6.84 5.773 6.93 5.971 ;
     RECT  7.74 5.881 8.406 5.971 ;
     RECT  10.515 5.729 10.797 5.971 ;
     RECT  9.144 5.971 9.162 6.007 ;
     RECT  0.396 5.845 0.486 6.043 ;
     RECT  4.284 5.881 6.066 6.043 ;
     RECT  6.84 5.971 8.406 6.043 ;
     RECT  9.144 6.007 9.234 6.091 ;
     RECT  0.36 6.043 0.486 6.115 ;
     RECT  10.224 5.971 10.797 6.235 ;
     RECT  2.34 5.971 3.438 6.241 ;
     RECT  4.284 6.043 8.406 6.241 ;
     RECT  10.152 6.235 10.797 6.275 ;
     RECT  0.36 6.115 0.522 6.385 ;
     RECT  2.34 6.241 8.406 6.421 ;
     RECT  9.144 6.091 9.27 6.421 ;
     RECT  0.36 6.385 0.558 6.475 ;
     RECT  0.108 6.475 0.558 6.583 ;
     RECT  0.108 6.583 1.17 6.605 ;
     RECT  2.34 6.421 9.27 6.655 ;
     RECT  0.18 6.605 1.17 6.719 ;
     RECT  2.304 6.655 9.27 6.809 ;
     RECT  0.18 6.719 0.558 7.133 ;
     RECT  2.304 6.809 8.406 7.231 ;
     RECT  10.515 6.275 10.797 7.501 ;
     RECT  11.52 5.729 17.19 7.501 ;
     RECT  2.232 7.231 8.406 7.579 ;
     RECT  2.196 7.579 8.406 7.591 ;
     RECT  10.515 7.501 17.19 7.661 ;
     RECT  2.196 7.591 8.766 7.691 ;
     RECT  9.684 7.159 9.702 7.771 ;
     RECT  2.196 7.691 8.226 7.799 ;
     RECT  10.515 7.661 17.082 7.805 ;
     RECT  15.912 7.805 17.082 7.853 ;
     RECT  9.072 7.771 9.702 7.861 ;
     RECT  10.515 7.805 15.174 7.861 ;
     RECT  0.216 7.133 0.558 8.011 ;
     RECT  0.18 8.011 0.558 8.155 ;
     RECT  0.144 8.155 0.558 8.203 ;
     RECT  0.144 8.203 1.17 8.299 ;
     RECT  0.144 8.299 1.206 8.311 ;
     RECT  0.144 8.311 1.242 8.347 ;
     RECT  15.984 7.853 17.082 8.381 ;
     RECT  2.232 7.799 8.226 8.429 ;
     RECT  16.416 8.381 17.082 8.491 ;
     RECT  0.108 8.347 1.242 8.537 ;
     RECT  2.268 8.429 8.226 8.581 ;
     RECT  9.072 7.861 15.174 8.581 ;
     RECT  0.108 8.537 1.17 8.924 ;
     RECT  16.416 8.491 17.118 8.957 ;
     RECT  0.144 8.924 1.17 9.005 ;
     RECT  16.596 8.957 17.118 9.013 ;
     RECT  2.268 8.581 15.174 9.149 ;
     RECT  6.696 9.149 15.174 9.239 ;
     RECT  0.18 9.005 1.17 9.389 ;
     RECT  0.18 9.389 0.414 9.629 ;
     RECT  16.596 9.013 17.19 9.691 ;
     RECT  0.18 9.629 0.378 9.739 ;
     RECT  1.152 9.389 1.17 9.787 ;
     RECT  2.268 9.149 5.886 9.787 ;
     RECT  8.964 9.239 15.174 9.851 ;
     RECT  16.524 9.691 17.19 9.883 ;
     RECT  6.696 9.239 8.19 9.931 ;
     RECT  16.452 9.883 17.19 9.931 ;
     RECT  6.624 9.931 8.19 10.021 ;
     RECT  0.144 9.739 0.378 10.157 ;
     RECT  16.272 9.931 17.19 10.165 ;
     RECT  1.152 9.787 5.886 10.201 ;
     RECT  6.624 10.021 8.226 10.201 ;
     RECT  16.056 10.165 17.19 10.205 ;
     RECT  16.2 10.205 17.19 10.516 ;
     RECT  1.152 10.201 8.226 10.633 ;
     RECT  9.072 9.851 15.174 10.633 ;
     RECT  16.2 10.516 17.262 11.281 ;
     RECT  16.02 11.281 17.262 11.326 ;
     RECT  1.152 10.633 15.174 11.371 ;
     RECT  15.984 11.326 17.262 11.371 ;
     RECT  1.152 11.371 17.262 11.552 ;
     RECT  1.152 11.552 8.91 11.705 ;
     RECT  9.648 11.552 17.262 11.741 ;
     RECT  0.144 10.157 0.306 11.777 ;
     RECT  9.648 11.741 16.326 11.789 ;
     RECT  15.984 11.789 16.326 11.837 ;
     RECT  1.404 11.705 8.91 12.209 ;
     RECT  0.144 11.777 0.27 12.245 ;
     RECT  17.064 11.741 17.262 12.281 ;
     RECT  9.648 11.789 15.174 12.325 ;
     RECT  0.18 12.245 0.27 12.515 ;
     RECT  1.404 12.209 8.226 12.551 ;
     RECT  8.964 12.325 15.174 12.587 ;
     RECT  2.34 12.551 8.226 12.659 ;
     RECT  2.376 12.659 8.226 12.749 ;
     RECT  0.252 12.515 0.27 12.785 ;
     RECT  8.964 12.587 9.774 12.821 ;
     RECT  9.648 12.821 9.774 12.857 ;
     RECT  2.376 12.749 8.097 13.019 ;
     RECT  9.648 12.857 9.738 13.019 ;
     RECT  9.72 13.019 9.738 13.055 ;
     RECT  15.984 11.837 16.254 13.091 ;
     RECT  2.415 13.019 8.097 13.289 ;
     RECT  17.1 12.281 17.262 13.289 ;
     RECT  1.404 12.551 1.422 13.325 ;
     RECT  10.515 12.587 15.174 13.595 ;
     RECT  7.236 13.289 8.097 13.631 ;
     RECT  17.244 13.289 17.262 13.703 ;
     RECT  2.415 13.289 6.246 13.829 ;
     RECT  10.515 13.595 11.502 13.829 ;
     RECT  10.515 13.829 10.854 13.937 ;
     RECT  2.415 13.829 3.87 13.973 ;
     RECT  15.984 13.091 16.002 14.009 ;
     RECT  2.415 13.973 3.546 14.099 ;
     RECT  12.456 13.595 15.174 14.099 ;
     RECT  2.415 14.099 3.402 14.135 ;
     RECT  12.456 14.099 12.474 14.369 ;
     RECT  13.215 14.099 15.174 14.639 ;
     RECT  13.215 14.639 13.662 14.711 ;
     RECT  14.472 14.639 15.174 14.819 ;
     RECT  2.415 14.135 2.697 14.867 ;
     RECT  5.115 13.829 5.397 14.867 ;
     RECT  7.815 13.631 8.097 14.867 ;
     RECT  10.515 13.937 10.797 14.867 ;
     RECT  13.215 14.711 13.497 14.867 ;
     RECT  14.724 14.819 15.174 14.909 ;
     RECT  14.724 14.909 14.742 14.945 ;
     RECT  2.415 14.867 2.505 15.137 ;
     RECT  5.115 14.867 5.205 15.137 ;
     RECT  7.815 14.867 7.905 15.137 ;
     RECT  10.515 14.867 10.605 15.137 ;
     RECT  13.215 14.867 13.305 15.137 ;
    LAYER M4 ;
     RECT  0.06 6.48 0.133 10.776 ;
     RECT  0.133 6.48 0.137 10.824 ;
     RECT  0.137 6.576 0.317 10.824 ;
     RECT  0.317 6.576 2.408 10.776 ;
     RECT  2.408 2.148 2.512 15.132 ;
     RECT  2.512 2.418 2.704 14.862 ;
     RECT  2.704 5.28 2.837 5.304 ;
     RECT  2.704 6.288 3.305 11.256 ;
     RECT  3.305 7.872 4.057 11.256 ;
     RECT  2.704 12.48 4.057 13.08 ;
     RECT  3.305 6.288 4.309 6.696 ;
     RECT  4.057 7.872 4.309 13.08 ;
     RECT  4.309 6.288 5.108 13.08 ;
     RECT  5.108 2.148 5.212 15.132 ;
     RECT  5.212 2.418 5.404 14.862 ;
     RECT  5.404 6.288 5.825 13.08 ;
     RECT  5.825 6.288 5.933 12.504 ;
     RECT  5.933 6.288 7.117 12.312 ;
     RECT  7.117 6.288 7.621 12.504 ;
     RECT  7.621 6 7.808 12.504 ;
     RECT  7.808 2.148 7.912 15.132 ;
     RECT  7.912 2.418 8.104 14.862 ;
     RECT  8.104 8.16 8.237 9.048 ;
     RECT  8.104 10.176 8.237 12.504 ;
     RECT  8.237 10.704 8.489 12.504 ;
     RECT  8.104 6.096 9.281 7.176 ;
     RECT  8.237 8.208 9.601 9.048 ;
     RECT  9.601 8.208 10.249 9.912 ;
     RECT  8.489 11.184 10.249 12.504 ;
     RECT  9.281 6.24 10.465 7.176 ;
     RECT  10.249 8.208 10.465 12.504 ;
     RECT  10.465 6.24 10.508 12.504 ;
     RECT  10.508 2.148 10.612 15.132 ;
     RECT  10.612 2.418 10.804 14.862 ;
     RECT  10.804 6.336 12.265 12.6 ;
     RECT  12.265 6 12.301 12.6 ;
     RECT  12.301 5.904 13.093 12.744 ;
     RECT  13.093 5.76 13.208 12.744 ;
     RECT  13.208 2.148 13.312 15.132 ;
     RECT  13.312 2.418 13.504 14.862 ;
     RECT  13.504 5.712 13.745 12.504 ;
     RECT  13.745 5.712 14.105 12.36 ;
     RECT  14.105 6 14.213 12.36 ;
     RECT  14.213 6.576 16.229 12.36 ;
     RECT  16.229 6.576 16.337 11.832 ;
     RECT  16.337 6.576 16.517 11.16 ;
     RECT  16.517 6.576 17.125 10.872 ;
     RECT  17.125 6.48 17.165 10.872 ;
     RECT  17.165 6.48 17.244 10.776 ;
    LAYER M5 ;
     RECT  2.4 2.137 2.52 2.151 ;
     RECT  5.1 2.137 5.22 2.151 ;
     RECT  7.8 2.137 7.92 2.151 ;
     RECT  10.5 2.137 10.62 2.151 ;
     RECT  13.2 2.137 13.32 2.151 ;
     RECT  2.4 2.151 2.712 5.269 ;
     RECT  10.5 2.151 10.812 6.229 ;
     RECT  2.4 5.269 2.808 6.565 ;
     RECT  10.176 6.229 10.812 6.611 ;
     RECT  7.8 2.151 8.112 7.381 ;
     RECT  16.944 7.093 16.968 7.573 ;
     RECT  16.56 7.573 16.968 7.619 ;
     RECT  16.56 7.619 16.584 8.435 ;
     RECT  5.1 2.151 5.412 8.677 ;
     RECT  13.2 2.151 13.512 8.677 ;
     RECT  2.4 6.565 2.904 8.723 ;
     RECT  12.864 8.677 13.512 8.915 ;
     RECT  4.704 8.677 5.412 9.011 ;
     RECT  2.4 8.723 2.856 9.395 ;
     RECT  13.2 8.915 13.512 9.493 ;
     RECT  0.288 8.245 0.312 9.539 ;
     RECT  13.2 9.493 13.704 9.635 ;
     RECT  0.144 10.597 0.168 10.835 ;
     RECT  17.088 10.645 17.112 10.883 ;
     RECT  5.1 9.011 5.412 11.509 ;
     RECT  5.1 11.509 5.592 12.083 ;
     RECT  7.296 7.381 8.112 12.083 ;
     RECT  2.4 9.395 2.712 15.129 ;
     RECT  5.1 12.083 5.412 15.129 ;
     RECT  7.8 12.083 8.112 15.129 ;
     RECT  10.5 6.611 10.812 15.129 ;
     RECT  13.2 9.635 13.512 15.129 ;
     RECT  2.4 15.129 2.52 15.143 ;
     RECT  5.1 15.129 5.22 15.143 ;
     RECT  7.8 15.129 7.92 15.143 ;
     RECT  10.5 15.129 10.62 15.143 ;
     RECT  13.2 15.129 13.32 15.143 ;
  END
END dsfd_stnh_86x1
END LIBRARY
